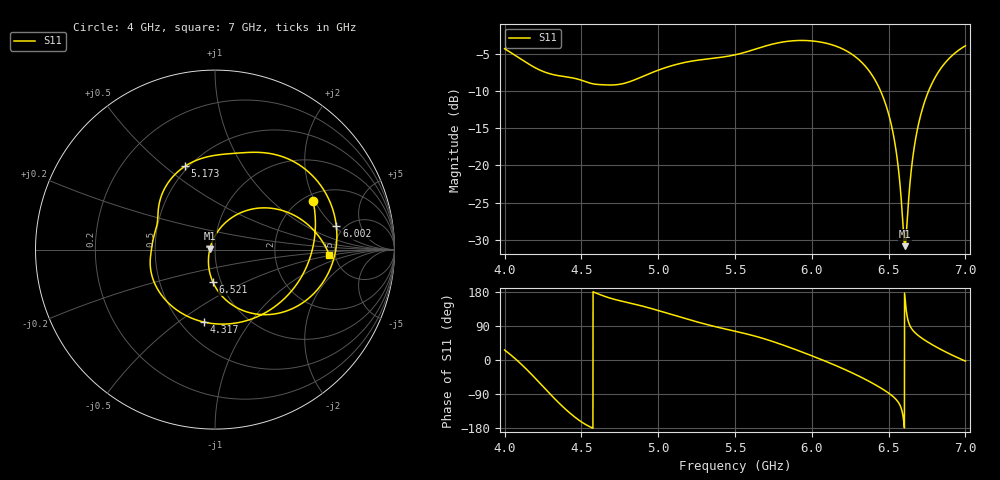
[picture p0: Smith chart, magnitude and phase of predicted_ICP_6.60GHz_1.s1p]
! ICP-predicted S11, target max centred GHz at -10 dB. Complex ensemble mean (passive and causal);
! its |S11| can differ slightly from the dB-domain mean reported in designs.csv.
!  Air_gap = 1.82mm
!  W_Patch = 13.02mm
!  L_Patch = 18.12mm
!  Sx = 0.38mm
!  Sy = 4.56mm
!  W_Patch1 = 13.17mm
!  WS = 1.08mm
!  Curve_Amp1 = 3.12mm
!  Extra = 6.74mm
# GHz S MA R 50
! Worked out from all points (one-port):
!   3001 points, 4 GHz to 7 GHz, reference 50 ohm
!   lowest |S11| = -30.9 dB at 6.606 GHz (marker M1), VSWR 1.06, Z = 47.3 + j0.578 ohm
!   |S11| at or under -10 dB: 6.448 GHz to 6.76 GHz (311.7 MHz wide, 4.72 % of centre)
!   S11 on the Smith chart (normalised r, x): 4 GHz: 2.25, +1.95; 4.317 GHz: 0.65, -0.63; 5.173 GHz: 0.48, +0.59; 6.002 GHz: 4.32, +2.13; 6.521 GHz: 0.92, -0.34; 7 GHz: 4.48, -0.49
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4  0.6106 26.4
4.092  0.5312 -4.9
4.186  0.4623 -42.4
4.251  0.4289 -70.3
4.317  0.4085 -98.4
4.375  0.3984 -121.7
4.495  0.3762 -161.9
4.75  0.3518 156.5
4.959  0.4215 135.4
5.125  0.4806 115.6
5.173  0.4935 109.9
5.5  0.5551 76.0
5.71  0.6415 53.5
5.875  0.6898 30.4
6.002  0.6885 10.8
6.125  0.6515 -9.3
6.25  0.5701 -31.6
6.415  0.3711 -65.7
6.521  0.1813 -93.7
6.559  0.105 -109.1
6.596  0.03638 -153.8
6.606  0.02865 167.7
6.625  0.04917 107.0
6.646  0.08974 85.2
6.669  0.1369 73.4
6.74  0.2788 51.2
6.852  0.4676 25.3
7  0.6386 -2.9
